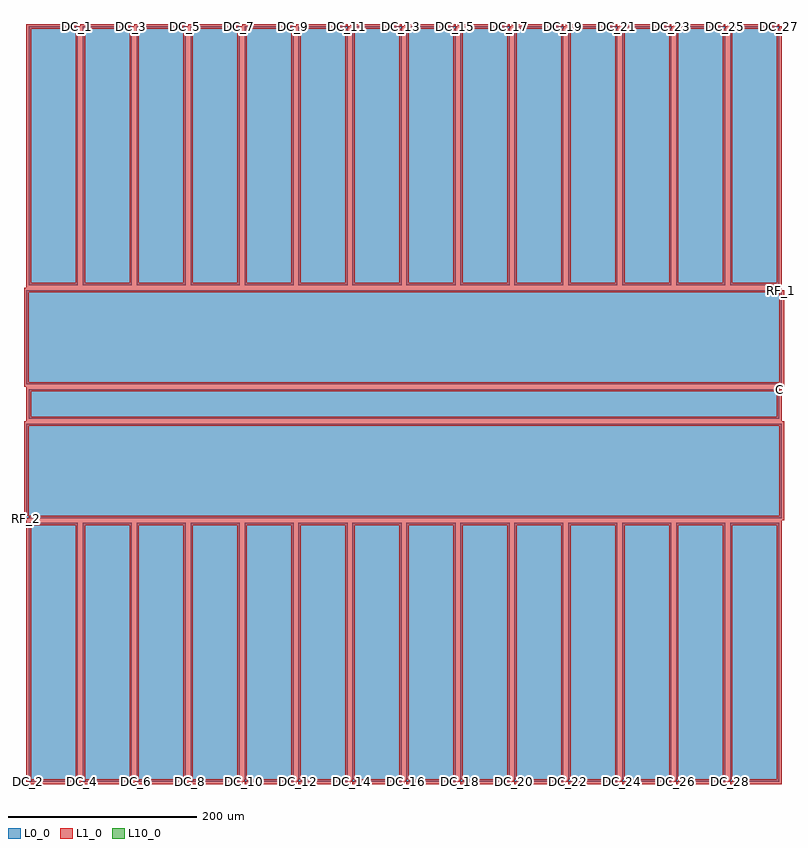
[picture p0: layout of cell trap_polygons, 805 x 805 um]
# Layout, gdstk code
import gdstk
lib = gdstk.Library(unit=1e-6, precision=1e-09)
def P(c, l, *ps):  # polygons
    for p in ps: c.add(gdstk.Polygon(p, *l))
L0_0 = (0, 0)
L1_0 = (1, 0)
L10_0 = (10, 0)

trap_polygons = lib.new_cell('trap_polygons')
P(trap_polygons, L0_0, [(345.357,-400),(345.357,-125.75),(397.5,-125.75),(397.5,-400),(345.357,-400)],
  [(397.5,400),(397.5,125.75),(345.357,125.75),(345.357,400),(397.5,400)],
  [(288.214,-400),(288.214,-125.75),(340.357,-125.75),(340.357,-400),(288.214,-400)],
  [(340.357,400),(340.357,125.75),(288.214,125.75),(288.214,400),(340.357,400)],
  [(231.071,-400),(231.071,-125.75),(283.214,-125.75),(283.214,-400),(231.071,-400)],
  [(283.214,400),(283.214,125.75),(231.071,125.75),(231.071,400),(283.214,400)],
  [(173.928,-400),(173.928,-125.75),(226.071,-125.75),(226.071,-400),(173.928,-400)],
  [(226.071,400),(226.071,125.75),(173.928,125.75),(173.928,400),(226.071,400)],
  [(116.786,-400),(116.786,-125.75),(168.928,-125.75),(168.928,-400),(116.786,-400)],
  [(168.928,400),(168.928,125.75),(116.786,125.75),(116.786,400),(168.928,400)],
  [(59.643,-400),(59.643,-125.75),(111.786,-125.75),(111.786,-400),(59.643,-400)],
  [(111.786,400),(111.786,125.75),(59.643,125.75),(59.643,400),(111.786,400)],
  [(2.5,-400),(2.5,-125.75),(54.643,-125.75),(54.643,-400),(2.5,-400)],
  [(54.643,400),(54.643,125.75),(2.5,125.75),(2.5,400),(54.643,400)],
  [(-54.643,-400),(-54.643,-125.75),(-2.5,-125.75),(-2.5,-400),(-54.643,-400)],
  [(-2.5,400),(-2.5,125.75),(-54.643,125.75),(-54.643,400),(-2.5,400)],
  [(-111.786,-400),(-111.786,-125.75),(-59.643,-125.75),(-59.643,-400),(-111.786,-400)],
  [(-59.643,400),(-59.643,125.75),(-111.786,125.75),(-111.786,400),(-59.643,400)],
  [(-168.929,-400),(-168.929,-125.75),(-116.786,-125.75),(-116.786,-400),(-168.929,-400)],
  [(-116.786,400),(-116.786,125.75),(-168.929,125.75),(-168.929,400),(-116.786,400)],
  [(-226.071,-400),(-226.071,-125.75),(-173.929,-125.75),(-173.929,-400),(-226.071,-400)],
  [(-173.929,400),(-173.929,125.75),(-226.071,125.75),(-226.071,400),(-173.929,400)],
  [(-283.214,-400),(-283.214,-125.75),(-231.071,-125.75),(-231.071,-400),(-283.214,-400)],
  [(-231.071,400),(-231.071,125.75),(-283.214,125.75),(-283.214,400),(-231.071,400)],
  [(-340.357,-400),(-340.357,-125.75),(-288.214,-125.75),(-288.214,-400),(-340.357,-400)],
  [(-288.214,400),(-288.214,125.75),(-340.357,125.75),(-340.357,400),(-288.214,400)],
  [(-397.5,-400),(-397.5,-125.75),(-345.357,-125.75),(-345.357,-400),(-397.5,-400)],
  [(-345.357,400),(-345.357,125.75),(-397.5,125.75),(-397.5,400),(-345.357,400)],
  [(397.5,15.75),(397.5,-15.75),(-397.5,-15.75),(-397.5,15.75),(397.5,15.75)],
  [(-400,-120.75),(-400,-20.75),(400,-20.75),(400,-120.75),(-400,-120.75)],
  [(400,120.75),(400,20.75),(-400,20.75),(-400,120.75),(400,120.75)])
P(trap_polygons, L1_0, [(342.857,-400),(347.857,-400),(347.857,-128.25),(395,-128.25),(395,-397.5),(345.357,-397.5),(345.357,-402.5),(400,-402.5),(400,-123.25),(342.857,-123.25)],
  [(400,400),(395,400),(395,128.25),(347.857,128.25),(347.857,397.5),(397.5,397.5),(397.5,402.5),(342.857,402.5),(342.857,123.25),(400,123.25)],
  [(285.714,-400),(290.714,-400),(290.714,-128.25),(337.857,-128.25),(337.857,-397.5),(288.214,-397.5),(288.214,-402.5),(342.857,-402.5),(342.857,-123.25),(285.714,-123.25)],
  [(342.857,400),(337.857,400),(337.857,128.25),(290.714,128.25),(290.714,397.5),(340.357,397.5),(340.357,402.5),(285.714,402.5),(285.714,123.25),(342.857,123.25)],
  [(228.571,-400),(233.571,-400),(233.571,-128.25),(280.714,-128.25),(280.714,-397.5),(231.071,-397.5),(231.071,-402.5),(285.714,-402.5),(285.714,-123.25),(228.571,-123.25)],
  [(285.714,400),(280.714,400),(280.714,128.25),(233.571,128.25),(233.571,397.5),(283.214,397.5),(283.214,402.5),(228.571,402.5),(228.571,123.25),(285.714,123.25)],
  [(171.428,-400),(176.428,-400),(176.428,-128.25),(223.571,-128.25),(223.571,-397.5),(173.928,-397.5),(173.928,-402.5),(228.571,-402.5),(228.571,-123.25),(171.428,-123.25)],
  [(228.571,400),(223.571,400),(223.571,128.25),(176.428,128.25),(176.428,397.5),(226.071,397.5),(226.071,402.5),(171.428,402.5),(171.428,123.25),(228.571,123.25)],
  [(114.286,-400),(119.286,-400),(119.286,-128.25),(166.428,-128.25),(166.428,-397.5),(116.786,-397.5),(116.786,-402.5),(171.428,-402.5),(171.428,-123.25),(114.286,-123.25)],
  [(171.428,400),(166.428,400),(166.428,128.25),(119.286,128.25),(119.286,397.5),(168.928,397.5),(168.928,402.5),(114.286,402.5),(114.286,123.25),(171.428,123.25)],
  [(57.143,-400),(62.143,-400),(62.143,-128.25),(109.286,-128.25),(109.286,-397.5),(59.643,-397.5),(59.643,-402.5),(114.286,-402.5),(114.286,-123.25),(57.143,-123.25)],
  [(114.286,400),(109.286,400),(109.286,128.25),(62.143,128.25),(62.143,397.5),(111.786,397.5),(111.786,402.5),(57.143,402.5),(57.143,123.25),(114.286,123.25)],
  [(0,-400),(5,-400),(5,-128.25),(52.143,-128.25),(52.143,-397.5),(2.5,-397.5),(2.5,-402.5),(57.143,-402.5),(57.143,-123.25),(0,-123.25)],
  [(57.143,400),(52.143,400),(52.143,128.25),(5,128.25),(5,397.5),(54.643,397.5),(54.643,402.5),(0,402.5),(0,123.25),(57.143,123.25)],
  [(-57.143,-400),(-52.143,-400),(-52.143,-128.25),(-5,-128.25),(-5,-397.5),(-54.643,-397.5),(-54.643,-402.5),(0,-402.5),(0,-123.25),(-57.143,-123.25)],
  [(0,400),(-5,400),(-5,128.25),(-52.143,128.25),(-52.143,397.5),(-2.5,397.5),(-2.5,402.5),(-57.143,402.5),(-57.143,123.25),(0,123.25)],
  [(-114.286,-400),(-109.286,-400),(-109.286,-128.25),(-62.143,-128.25),(-62.143,-397.5),(-111.786,-397.5),(-111.786,-402.5),(-57.143,-402.5),(-57.143,-123.25),(-114.286,-123.25)],
  [(-57.143,400),(-62.143,400),(-62.143,128.25),(-109.286,128.25),(-109.286,397.5),(-59.643,397.5),(-59.643,402.5),(-114.286,402.5),(-114.286,123.25),(-57.143,123.25)],
  [(-171.429,-400),(-166.429,-400),(-166.429,-128.25),(-119.286,-128.25),(-119.286,-397.5),(-168.929,-397.5),(-168.929,-402.5),(-114.286,-402.5),(-114.286,-123.25),(-171.429,-123.25)],
  [(-114.286,400),(-119.286,400),(-119.286,128.25),(-166.429,128.25),(-166.429,397.5),(-116.786,397.5),(-116.786,402.5),(-171.429,402.5),(-171.429,123.25),(-114.286,123.25)],
  [(-228.571,-400),(-223.571,-400),(-223.571,-128.25),(-176.429,-128.25),(-176.429,-397.5),(-226.071,-397.5),(-226.071,-402.5),(-171.429,-402.5),(-171.429,-123.25),(-228.571,-123.25)],
  [(-171.429,400),(-176.429,400),(-176.429,128.25),(-223.571,128.25),(-223.571,397.5),(-173.929,397.5),(-173.929,402.5),(-228.571,402.5),(-228.571,123.25),(-171.429,123.25)],
  [(-285.714,-400),(-280.714,-400),(-280.714,-128.25),(-233.571,-128.25),(-233.571,-397.5),(-283.214,-397.5),(-283.214,-402.5),(-228.571,-402.5),(-228.571,-123.25),(-285.714,-123.25)],
  [(-228.571,400),(-233.571,400),(-233.571,128.25),(-280.714,128.25),(-280.714,397.5),(-231.071,397.5),(-231.071,402.5),(-285.714,402.5),(-285.714,123.25),(-228.571,123.25)],
  [(-342.857,-400),(-337.857,-400),(-337.857,-128.25),(-290.714,-128.25),(-290.714,-397.5),(-340.357,-397.5),(-340.357,-402.5),(-285.714,-402.5),(-285.714,-123.25),(-342.857,-123.25)],
  [(-285.714,400),(-290.714,400),(-290.714,128.25),(-337.857,128.25),(-337.857,397.5),(-288.214,397.5),(-288.214,402.5),(-342.857,402.5),(-342.857,123.25),(-285.714,123.25)],
  [(-400,-400),(-395,-400),(-395,-128.25),(-347.857,-128.25),(-347.857,-397.5),(-397.5,-397.5),(-397.5,-402.5),(-342.857,-402.5),(-342.857,-123.25),(-400,-123.25)],
  [(-342.857,400),(-347.857,400),(-347.857,128.25),(-395,128.25),(-395,397.5),(-345.357,397.5),(-345.357,402.5),(-400,402.5),(-400,123.25),(-342.857,123.25)],
  [(400,15.75),(395,15.75),(395,-13.25),(-395,-13.25),(-395,13.25),(397.5,13.25),(397.5,18.25),(-400,18.25),(-400,-18.25),(400,-18.25)],
  [(-402.5,-120.75),(-397.5,-120.75),(-397.5,-23.25),(397.5,-23.25),(397.5,-118.25),(-400,-118.25),(-400,-123.25),(402.5,-123.25),(402.5,-18.25),(-402.5,-18.25)],
  [(402.5,120.75),(397.5,120.75),(397.5,23.25),(-397.5,23.25),(-397.5,118.25),(400,118.25),(400,123.25),(-402.5,123.25),(-402.5,18.25),(402.5,18.25)])
P(trap_polygons, L10_0, [(0,0),(0,0),(0,0),(0,0)])
trap_polygons.add(gdstk.Label('DC_28', (345.357,-400), layer=2, texttype=0))
trap_polygons.add(gdstk.Label('DC_27', (397.5,400), layer=2, texttype=0))
trap_polygons.add(gdstk.Label('DC_26', (288.214,-400), layer=2, texttype=0))
trap_polygons.add(gdstk.Label('DC_25', (340.357,400), layer=2, texttype=0))
trap_polygons.add(gdstk.Label('DC_24', (231.071,-400), layer=2, texttype=0))
trap_polygons.add(gdstk.Label('DC_23', (283.214,400), layer=2, texttype=0))
trap_polygons.add(gdstk.Label('DC_22', (173.928,-400), layer=2, texttype=0))
trap_polygons.add(gdstk.Label('DC_21', (226.071,400), layer=2, texttype=0))
trap_polygons.add(gdstk.Label('DC_20', (116.786,-400), layer=2, texttype=0))
trap_polygons.add(gdstk.Label('DC_19', (168.928,400), layer=2, texttype=0))
trap_polygons.add(gdstk.Label('DC_18', (59.643,-400), layer=2, texttype=0))
trap_polygons.add(gdstk.Label('DC_17', (111.786,400), layer=2, texttype=0))
trap_polygons.add(gdstk.Label('DC_16', (2.5,-400), layer=2, texttype=0))
trap_polygons.add(gdstk.Label('DC_15', (54.643,400), layer=2, texttype=0))
trap_polygons.add(gdstk.Label('DC_14', (-54.643,-400), layer=2, texttype=0))
trap_polygons.add(gdstk.Label('DC_13', (-2.5,400), layer=2, texttype=0))
trap_polygons.add(gdstk.Label('DC_12', (-111.786,-400), layer=2, texttype=0))
trap_polygons.add(gdstk.Label('DC_11', (-59.643,400), layer=2, texttype=0))
trap_polygons.add(gdstk.Label('DC_10', (-168.929,-400), layer=2, texttype=0))
trap_polygons.add(gdstk.Label('DC_9', (-116.786,400), layer=2, texttype=0))
trap_polygons.add(gdstk.Label('DC_8', (-226.071,-400), layer=2, texttype=0))
trap_polygons.add(gdstk.Label('DC_7', (-173.929,400), layer=2, texttype=0))
trap_polygons.add(gdstk.Label('DC_6', (-283.214,-400), layer=2, texttype=0))
trap_polygons.add(gdstk.Label('DC_5', (-231.071,400), layer=2, texttype=0))
trap_polygons.add(gdstk.Label('DC_4', (-340.357,-400), layer=2, texttype=0))
trap_polygons.add(gdstk.Label('DC_3', (-288.214,400), layer=2, texttype=0))
trap_polygons.add(gdstk.Label('DC_2', (-397.5,-400), layer=2, texttype=0))
trap_polygons.add(gdstk.Label('DC_1', (-345.357,400), layer=2, texttype=0))
trap_polygons.add(gdstk.Label('C', (397.5,15.75), layer=2, texttype=0))
trap_polygons.add(gdstk.Label('RF_2', (-400,-120.75), layer=2, texttype=0))
trap_polygons.add(gdstk.Label('RF_1', (400,120.75), layer=2, texttype=0))

lib.write_gds('trap_polygons.gds')
